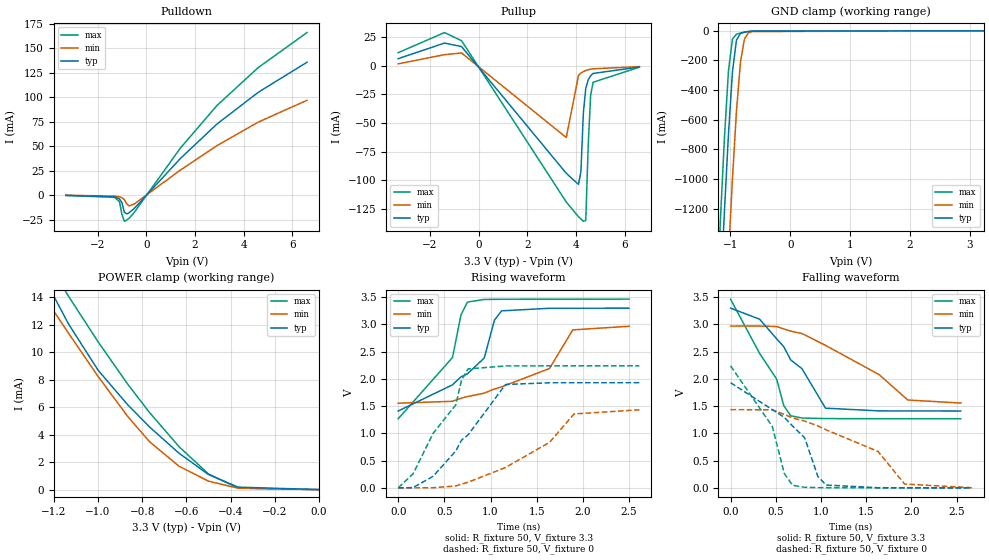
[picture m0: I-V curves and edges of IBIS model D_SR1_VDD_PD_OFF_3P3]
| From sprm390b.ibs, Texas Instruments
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|   Model Cell D_SR1_VDD_PD_OFF_3P3
|SR0_VDD_SR1_VDD_PD_OFF_3P3
[Model]   D_SR1_VDD_PD_OFF_3P3
Model_type   I/O
Polarity   Non-Inverting
Enable   Active-Low
Vinl =  0.8V
Vinh =  2V
Cref =  5.0000pF
Rref =  100.0000M
Vref =  0V
Vmeas =  1.65
C_comp   2.113745p   2.040636p   2.247812p
[Model Spec]
Vinl   0.8V   0.8V   0.8V
Vinh   2V   2V   2V
[Temperature Range]   25   125   -40
[Voltage Range]   3.3   2.97   3.465
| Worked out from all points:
|   slope of the pulldown table from 0 to 0.495 V, typ, clamps not added: 36.4 ohm
|   slope of the pullup table from 0 to 0.495 V, typ, clamps not added: 34.9 ohm
|   GND clamp passes 1 mA (typ) near -0.57 V on its own axis
|   POWER clamp passes 1 mA (typ) near -0.49 V on its own axis
|   rising waveform, R_fixture 50, V_fixture 3.3: 20-80 % time 540ps typ, 709ps min, 444ps max; typ from 1.41 V to 3.3 V
|   rising waveform, R_fixture 50, V_fixture 0: 20-80 % time 549ps typ, 739ps min, 445ps max; typ from 0 V to 1.93 V
|   falling waveform, R_fixture 50, V_fixture 3.3: 20-80 % time 516ps typ, 825ps min, 401ps max; typ from 3.3 V to 1.41 V
|   falling waveform, R_fixture 50, V_fixture 0: 20-80 % time 526ps typ, 842ps min, 409ps max; typ from 1.93 V to 0.001 V
[POWER_clamp]
|   voltage   I(typ)   I(min)   I(max)
-3.3V     86.08mA    64.51mA    104.3mA
-1.267V   16.23mA    14.61mA    17.94mA
-1.233V   15.14mA    13.79mA    16.86mA
-1.2V     14.07mA    12.98mA    15.86mA
-1.133V   12.04mA    11.37mA    14.06mA
-1V       8.693mA    8.239mA    10.76mA
-866.7mV  6.192mA    5.342mA    7.695mA
-766.7mV  4.556mA    3.483mA    5.603mA
-633.3mV  2.644mA    1.698mA    3.12mA
-500mV    1.095mA    613.6uA    1.135mA
-366.7mV  182uA      101.9uA    111.5uA
-11.55fV  514.4nA    479.6nA    539.8nA
[Pulldown]
|   voltage   I(typ)   I(min)   I(max)
-3.3V     -240.7uA   -171.6uA   -267.5uA
-1.3V     -1.697mA   -968uA     -2.239mA
-1.1V     -3.762mA   -1.687mA   -6.637mA
-1V       -7.728mA   -2.567mA   -19.64mA
-900mV    -17.44mA   -4.637mA   -26.73mA
-800mV    -19.19mA   -8.992mA   -25.39mA
-700mV    -17.88mA   -11mA      -23.57mA
-500mV    -13.74mA   -9.146mA   -17.83mA
1.4V      37.42mA    25.57mA    48.03mA
2.9V      72.6mA     50.52mA    91.53mA
4.6V      105.1mA    74.64mA    130.4mA
6.6V      135.8mA    96.92mA    166.1mA
[Pullup]
|   voltage   I(typ)   I(min)   I(max)
-3.3V     6.015mA    1.488mA    11.26mA
-1.4V     19.63mA    9.503mA    28.79mA
-700mV    16.55mA    11.01mA    21.71mA
3.6V      -93.97mA   -62.76mA   -119mA
4.1V      -103.6mA   -8.736mA   -131.8mA
4.2V      -92.66mA   -6.551mA   -133.7mA
4.3V      -41.55mA   -5.211mA   -135.8mA
4.4V      -19.91mA   -4.314mA   -135.1mA
4.5V      -12.4mA    -3.675mA   -69.72mA
4.6V      -8.869mA   -3.197mA   -25.86mA
4.7V      -6.864mA   -2.828mA   -14.55mA
6.6V      -1.25mA    -873.6uA   -1.41mA
[GND_clamp]
|   voltage   I(typ)   I(min)   I(max)
-3.3V     -22.46A    -23.25A    -22.02A
-1.233V   -2.372A    -3.255A    -1.856A
-1.167V   -1.78A     -2.658A    -1.268A
-1.1V     -1.214A    -2.077A    -719.3mA
-1.033V   -694.9mA   -1.519A    -269mA
-966.7mV  -277.7mA   -998.2mA   -54.76mA
-900mV    -62.9mA    -543.8mA   -23.12mA
-833.3mV  -17.79mA   -212.7mA   -15.05mA
-766.7mV  -9.259mA   -55.44mA   -9.031mA
-700mV    -5.097mA   -13.91mA   -4.436mA
-633.3mV  -2.354mA   -4.853mA   -1.588mA
3.233V    494nA      13.48uA    483nA
[Ramp]
| variable   typ   min   max
dV/dt_f   1.523549/0.6827238n   1.142886/1.116788n   1.769367/0.5163791n
dV/dt_r   1.547078/0.694645n   1.15064/0.965876n   1.794788/0.5501428n
R_load = 50
[Rising Waveform]
R_fixture = 50
V_fixture = 3.3
V_fixture_min = 2.97
V_fixture_max = 3.465
|   time   V(typ)   V(min)   V(max)
0s        1.411V     1.554V     1.269V
588ps     1.892V     1.59V      2.394V
679ps     2.038V     1.645V     3.174V
749ps     2.093V     1.676V     3.411V
931ps     2.383V     1.739V     3.459V
1.043ns   3.083V     1.816V     3.461V
1.12ns    3.25V      1.855V     3.462V
1.638ns   3.297V     2.191V     3.464V
1.89ns    3.298V     2.9V       3.464V
2.499ns   3.299V     2.967V     3.465V
[Rising Waveform]
R_fixture = 50
V_fixture = 0
V_fixture_min = 0
V_fixture_max = 0
|   time   V(typ)   V(min)   V(max)
0s        5.618uV    6.879uV    4.844uV
161ps     4.617mV    -39.37uV   258.5mV
378ps     212.5mV    2.905mV    1.001V
623ps     676.8mV    34.28mV    1.523V
686ps     876.2mV    69.87mV    1.98V
756ps     971.5mV    102.7mV    2.184V
1.162ns   1.898V     373.9mV    2.238V
1.638ns   1.929V     834.8mV    2.24V
1.904ns   1.93V      1.357V     2.241V
2.611ns   1.931V     1.433V     2.241V
[Falling Waveform]
R_fixture = 50
V_fixture = 3.3
V_fixture_min = 2.97
V_fixture_max = 3.465
|   time   V(typ)   V(min)   V(max)
0s        3.3V       2.97V      3.465V
322ps     3.096V     2.971V     2.467V
511ps     2.734V     2.962V     1.993V
588ps     2.594V     2.919V     1.513V
665ps     2.35V      2.878V     1.324V
791ps     2.186V     2.833V     1.282V
1.05ns    1.463V     2.616V     1.272V
1.645ns   1.413V     2.077V     1.27V
1.96ns    1.412V     1.613V     1.269V
2.548ns   1.411V     1.557V     1.269V
[Falling Waveform]
R_fixture = 50
V_fixture = 0
V_fixture_min = 0
V_fixture_max = 0
|   time   V(typ)   V(min)   V(max)
0s        1.931V     1.436V     2.241V
462ps     1.436V     1.434V     1.127V
595ps     1.295V     1.348V     263.1mV
686ps     1.135V     1.284V     47.65mV
819ps     922.6mV    1.226V     10.72mV
966ps     209.4mV    1.137V     5.024mV
1.057ns   52.32mV    1.066V     3.839mV
1.631ns   2.764mV    668.9mV    1.175mV
1.925ns   1.693mV    70.24mV    678.1uV
2.667ns   681.7uV    3mV        227.6uV
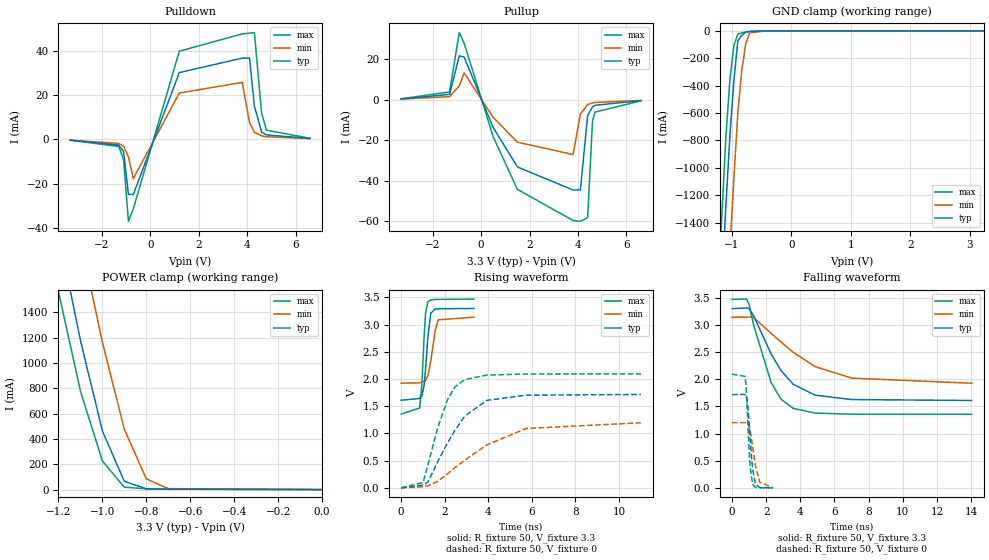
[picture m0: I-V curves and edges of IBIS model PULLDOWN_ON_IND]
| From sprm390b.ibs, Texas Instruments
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|   Model Cell PULLDOWN_ON_IND
[Model]   PULLDOWN_ON_IND
Model_type   I/O
Polarity   Non-Inverting
Enable   Active-Low
Vinl =  0.8
Vinh =  2
Cref =  15.0000pF
Rref =  100.0000M
Vref =  0V
Vmeas =  1.65
C_comp   0.8695239p   0.8584917p   0.8767336p
[Model Spec]
Vinl   0.8   0.8   0.8
Vinh   2   2   2
[Temperature Range]   25   125   -40
[Voltage Range]   3.3   3.14   3.47
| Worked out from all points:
|   slope of the pulldown table from 0 to 0.495 V, typ, clamps not added: 30.2 ohm
|   slope of the pullup table from 0 to 0.495 V, typ, clamps not added: 36.2 ohm
|   GND clamp passes 1 mA (typ) near -0.57 V on its own axis
|   POWER clamp passes 1 mA (typ) near -0.51 V on its own axis
|   rising waveform, R_fixture 50, V_fixture 3.3: 20-80 % time 196ps typ, 271ps min, 158ps max; typ from 1.61 V to 3.3 V
|   rising waveform, R_fixture 50, V_fixture 0: 20-80 % time 1.52ns typ, 2.63ns min, 970ps max; typ from 0 V to 1.72 V
|   falling waveform, R_fixture 50, V_fixture 3.3: 20-80 % time 1.92ns typ, 3.21ns min, 1.31ns max; typ from 3.3 V to 1.61 V
|   falling waveform, R_fixture 50, V_fixture 0: 20-80 % time 245ps typ, 360ps min, 192ps max; typ from 1.72 V to 0.002 V
[POWER_clamp]
|   voltage   I(typ)   I(min)   I(max)
-3.3V     22.37A     23.12A     21.96A
-1.2V     2.026A     2.853A     1.569A
-1.167V   1.745A     2.562A     1.307A
-1.133V   1.464A     2.272A     1.044A
-1.1V     1.183A     1.981A     781.9mA
-1.067V   943.8mA    1.709A     597.3mA
-1.033V   704.5mA    1.438A     412.6mA
-1V       465.3mA    1.167A     228mA
-900mV    65.82mA    478.8mA    19.1mA
-800mV    6.559mA    85.44mA    6.233mA
-700mV    3.243mA    7.603mA    3.974mA
-11.55fV  93.69uA    58.38uA    142.7uA
[Pulldown]
|   voltage   I(typ)   I(min)   I(max)
-3.3V     -379.4uA   -343.9uA   -387.1uA
-1.3V     -2.568mA   -1.817mA   -3.182mA
-1.1V     -5.533mA   -3.077mA   -9.169mA
-900mV    -24.8mA    -7.917mA   -37.01mA
-700mV    -24.92mA   -17.73mA   -31.42mA
1.2V      30.21mA    20.95mA    39.85mA
3.8V      36.73mA    25.77mA    47.69mA
4.1V      36.79mA    7.552mA    48.04mA
4.3V      15.06mA    3.224mA    48.29mA
4.6V      3.307mA    1.638mA    11.86mA
4.8V      2.043mA    1.221mA    4.171mA
6.6V      436uA      362.2uA    504.7uA
[Pullup]
|   voltage   I(typ)   I(min)   I(max)
-3.3V     352.6uA    265.5uA    392uA
-1.3V     2.559mA    1.454mA    3.793mA
-900mV    21.62mA    6.762mA    33.1mA
-700mV    21.01mA    13.2mA     27.87mA
500mV     -13.79mA   -8.778mA   -18.37mA
1.5V      -33.25mA   -21.03mA   -44.32mA
3.8V      -44.66mA   -27.13mA   -59.69mA
4.1V      -44.61mA   -7.119mA   -60.09mA
4.4V      -7.897mA   -2.442mA   -58.25mA
4.6V      -3.604mA   -1.655mA   -10.86mA
4.7V      -2.803mA   -1.422mA   -6.172mA
6.6V      -515.4uA   -377.6uA   -600.5uA
[GND_clamp]
|   voltage   I(typ)   I(min)   I(max)
-3.3V     -22.52A    -23.33A    -22.07A
-1.233V   -2.436A    -3.336A    -1.911A
-1.167V   -1.845A    -2.739A    -1.328A
-1.1V     -1.269A    -2.151A    -766.5mA
-1.033V   -763.9mA   -1.597A    -354.9mA
-966.7mV  -365.3mA   -1.079A    -107.2mA
-900mV    -73.59mA   -596.9mA   -23.38mA
-833.3mV  -32.67mA   -287.4mA   -15.4mA
-766.7mV  -9.715mA   -93.52mA   -8.973mA
-700mV    -4.738mA   -15.15mA   -4.098mA
-433.3mV  -102.5uA   -290.5uA   -69.12uA
3.233V    93.67uA    58.63uA    142.6uA
[Ramp]
| variable   typ   min   max
dV/dt_f   1.02374/1.926598n   0.737575/3.244975n   1.279266/1.316571n
dV/dt_r   1.030118/1.522336n   0.7199978/2.644106n   1.255922/0.9676829n
R_load = 50
[Rising Waveform]
R_fixture = 50
V_fixture = 3.3
V_fixture_min = 3.14
V_fixture_max = 3.47
|   time   V(typ)   V(min)   V(max)
0s        1.609V     1.923V     1.354V
848ps     1.642V     1.929V     1.467V
948ps     1.683V     1.941V     1.875V
1.052ns   1.874V     1.954V     2.753V
1.12ns    2.174V     1.971V     3.209V
1.224ns   2.754V     2.053V     3.415V
1.36ns    3.209V     2.326V     3.453V
1.564ns   3.285V     2.894V     3.46V
1.7ns     3.289V     3.087V     3.462V
3.344ns   3.296V     3.135V     3.467V
[Rising Waveform]
R_fixture = 50
V_fixture = 0
V_fixture_min = 0
V_fixture_max = 0
|   time   V(typ)   V(min)   V(max)
0s        97.34nV    406.4nV    8.356nV
1.008ns   51.54mV    21.89mV    99mV
1.232ns   107mV      40.68mV    429.3mV
1.68ns    481.7mV    118.7mV    1.104V
2.132ns   827.1mV    258.8mV    1.62V
2.468ns   1.055V     371.2mV    1.855V
2.92ns    1.317V     507.4mV    1.988V
3.928ns   1.607V     788mV      2.072V
5.728ns   1.702V     1.09V      2.091V
11.01ns   1.716V     1.196V     2.093V
[Falling Waveform]
R_fixture = 50
V_fixture = 3.3
V_fixture_min = 3.14
V_fixture_max = 3.47
|   time   V(typ)   V(min)   V(max)
0s        3.298V     3.139V     3.468V
856ps     3.311V     3.139V     3.473V
1ns       3.301V     3.148V     3.376V
1.284ns   3.156V     3.132V     2.977V
2.288ns   2.467V     2.844V     1.943V
2.864ns   2.163V     2.687V     1.633V
3.58ns    1.908V     2.496V     1.464V
4.868ns   1.706V     2.231V     1.377V
7.02ns    1.625V     2.02V      1.356V
14.04ns   1.609V     1.926V     1.354V
[Falling Waveform]
R_fixture = 50
V_fixture = 0
V_fixture_min = 0
V_fixture_max = 0
|   time   V(typ)   V(min)   V(max)
0s        1.716V     1.2V       2.093V
760ps     1.721V     1.2V       2.053V
832ps     1.688V     1.206V     1.849V
908ps     1.562V     1.199V     1.351V
980ps     1.301V     1.162V     825.2mV
1.056ns   933.4mV    1.074V     414.6mV
1.204ns   354.8mV    773.8mV    67.14mV
1.376ns   71.13mV    401.4mV    9.308mV
1.624ns   7.627mV    104.3mV    3.273mV
2.408ns   1.889mV    3.168mV    1.257mV
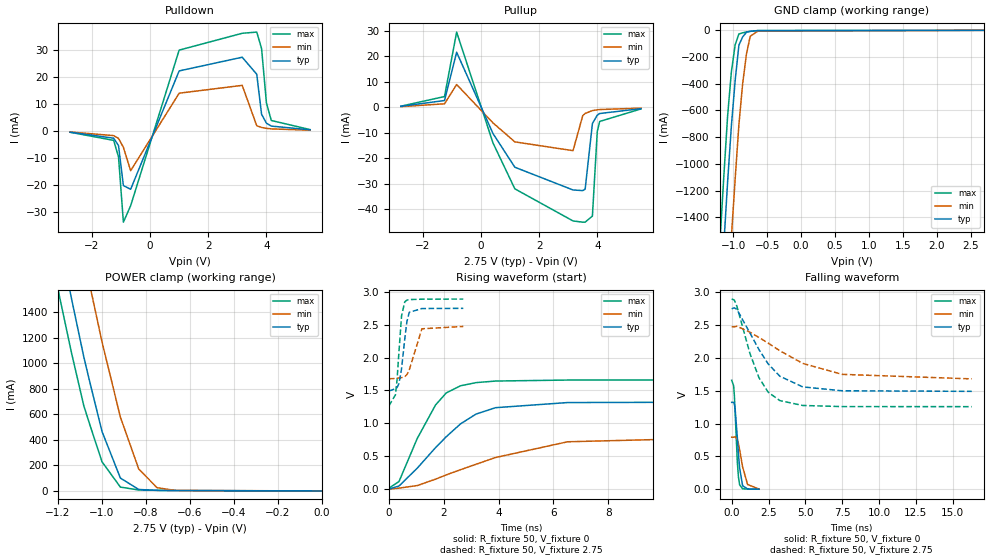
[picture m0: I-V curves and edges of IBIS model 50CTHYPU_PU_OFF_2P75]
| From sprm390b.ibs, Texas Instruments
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|   Model Cell 50CTHYPU_PU_OFF_2P75
|BC3350CTHYPU_PU_OFF_2P75
[Model]   50CTHYPU_PU_OFF_2P75
Model_type   I/O
Polarity   Non-Inverting
Enable   Active-Low
Vinl =  0.7V
Vinh =  1.7V
Cref =  15.0000pF
Rref =  100.0000M
Vref =  0V
Vmeas =  1.375
C_comp   0.8815254p   0.8700002p   0.8886429p
[Model Spec]
Vinl   0.7V   0.7V   0.7V
Vinh   1.7V   1.7V   1.7V
[Temperature Range]   25   125   -40
[Voltage Range]   2.75   2.475   2.89
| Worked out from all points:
|   slope of the pulldown table from 0 to 0.412 V, typ, clamps not added: 34.2 ohm
|   slope of the pullup table from 0 to 0.412 V, typ, clamps not added: 40.5 ohm
|   GND clamp passes 1 mA (typ) near -0.59 V on its own axis
|   POWER clamp passes 1 mA (typ) near -0.52 V on its own axis
|   rising waveform, R_fixture 50, V_fixture 0: 20-80 % time 1.9ns typ, 3.45ns min, 1.19ns max; typ from 0.002 V to 1.32 V
|   rising waveform, R_fixture 50, V_fixture 2.75: 20-80 % time 207ps typ, 302ps min, 164ps max; typ from 1.49 V to 2.75 V
|   falling waveform, R_fixture 50, V_fixture 0: 20-80 % time 263ps typ, 414ps min, 202ps max; typ from 1.32 V to 0.001 V
|   falling waveform, R_fixture 50, V_fixture 2.75: 20-80 % time 2.21ns typ, 3.92ns min, 1.52ns max; typ from 2.75 V to 1.49 V
[POWER_clamp]
|   voltage   I(typ)   I(min)   I(max)
-2.75V    16.94A     17.72A     16.52A
-1.194V   1.981A     2.806A     1.529A
-1.139V   1.509A     2.319A     1.084A
-1.083V   1.051A     1.84A      668.4mA
-1.056V   856mA      1.616A     521.6mA
-1.028V   660.7mA    1.391A     374.8mA
-1V       465.3mA    1.167A     228mA
-916.7mV  101mA      578.9mA    30.09mA
-833.3mV  11.44mA    171.8mA    7.269mA
-750mV    4.145mA    25.43mA    4.878mA
-666.7mV  2.649mA    3.757mA    3.2mA
0V        162.7pA    10.29nA    5.769pA
[Pulldown]
|   voltage   I(typ)   I(min)   I(max)
-2.75V    -442uA     -372.3uA   -461.5uA
-1.25V    -2.654mA   -1.707mA   -3.464mA
-1.083V   -5.414mA   -2.743mA   -9.571mA
-916.7mV  -20.11mA   -6.002mA   -33.59mA
-666.7mV  -21.47mA   -14.63mA   -27.52mA
1V        22.12mA    13.91mA    29.78mA
3.167V    27.16mA    16.8mA     35.98mA
3.667V    20.89mA    1.926mA    36.42mA
3.833V    6.158mA    1.295mA    30.36mA
4V        2.871mA    968.4uA    10.33mA
4.167V    1.802mA    770.5uA    3.863mA
5.5V      426.6uA    287.2uA    512.6uA
[Pullup]
|   voltage   I(typ)   I(min)   I(max)
-2.75V    418.2uA    298uA      474.9uA
-1.25V    2.701mA    1.416mA    4.261mA
-833.3mV  21.66mA    8.993mA    29.57mA
416.7mV   -10.28mA   -6.093mA   -13.97mA
1.167V    -23.49mA   -13.53mA   -31.97mA
3.167V    -32.42mA   -16.99mA   -44.58mA
3.5V      -32.66mA   -3.265mA   -45.07mA
3.583V    -32.13mA   -2.367mA   -45.05mA
3.833V    -6.324mA   -1.256mA   -42.67mA
4V        -3.056mA   -947.9uA   -9.45mA
4.083V    -2.401mA   -843.3uA   -5.52mA
5.5V      -494.4uA   -288.5uA   -602.6uA
[GND_clamp]
|   voltage   I(typ)   I(min)   I(max)
-2.75V    -17.09A    -17.92A    -16.63A
-1.194V   -2.087A    -2.985A    -1.564A
-1.139V   -1.603A    -2.493A    -1.092A
-1.083V   -1.133A    -2.009A    -639.3mA
-1.028V   -718.3mA   -1.55A     -312.4mA
-972.2mV  -377.6mA   -1.115A    -108.5mA
-916.7mV  -110.7mA   -705.2mA   -27.3mA
-861.1mV  -49.11mA   -398.2mA   -18.78mA
-805.6mV  -14.74mA   -178.1mA   -12.09mA
-750mV    -7.591mA   -44.83mA   -7.219mA
-638.9mV  -2.45mA    -6.091mA   -1.79mA
2.694V    -702.7pA   3.82uA     -24.74pA
[Ramp]
| variable   typ   min   max
dV/dt_f  0.7639975/2.221425n   0.484314/3.981112n   0.9885609/1.527353n
dV/dt_r  0.7939505/1.902615n   0.4756004/3.465002n   0.995026/1.20094n
R_load = 50
[Rising Waveform]
R_fixture = 50
V_fixture = 0
V_fixture_min = 0
V_fixture_max = 0
|   time   V(typ)   V(min)   V(max)
0s        1.783mV    -423.2uV   15.25mV
369ps     47.28mV    15.33mV    115.1mV
1.035ns   318.9mV    54.42mV    770.3mV
1.701ns   630.6mV    151.4mV    1.279V
2.091ns   796.5mV    216.3mV    1.462V
2.613ns   992.2mV    295.6mV    1.571V
3.177ns   1.141V     378mV      1.619V
3.888ns   1.238V     480.6mV    1.643V
6.516ns   1.316V     719.9mV    1.658V
13.17ns   1.323V     789.7mV    1.658V
[Rising Waveform]
R_fixture = 50
V_fixture = 2.75
V_fixture_min = 2.475
V_fixture_max = 2.89
|   time   V(typ)   V(min)   V(max)
0s        1.491V     1.678V     1.264V
240ps     1.526V     1.682V     1.433V
297ps     1.543V     1.686V     1.655V
369ps     1.607V     1.69V      2.093V
462ps     1.828V     1.694V     2.631V
579ps     2.278V     1.708V     2.846V
657ps     2.546V     1.741V     2.873V
744ps     2.688V     1.812V     2.881V
1.203ns   2.745V     2.437V     2.887V
2.712ns   2.748V     2.473V     2.889V
[Falling Waveform]
R_fixture = 50
V_fixture = 0
V_fixture_min = 0
V_fixture_max = 0
|   time   V(typ)   V(min)   V(max)
0s        1.323V     792.3mV    1.66V
132ps     1.324V     792.8mV    1.577V
183ps     1.294V     796.6mV    1.421V
234ps     1.223V     800.6mV    1.17V
384ps     782.4mV    758.4mV    408.7mV
459ps     535.2mV    693.9mV    185.2mV
537ps     324.1mV    604.2mV    67.81mV
741ps     52.77mV    341.3mV    6.665mV
1.077ns   3.649mV    72.65mV    1.896mV
1.851ns   1.319mV    2.486mV    950.3uV
[Falling Waveform]
R_fixture = 50
V_fixture = 2.75
V_fixture_min = 2.475
V_fixture_max = 2.89
|   time   V(typ)   V(min)   V(max)
0s        2.749V     2.475V     2.897V
177ps     2.764V     2.475V     2.883V
354ps     2.739V     2.483V     2.786V
1.236ns   2.382V     2.393V     2.07V
1.854ns   2.126V     2.311V     1.698V
2.478ns   1.909V     2.226V     1.478V
3.273ns   1.721V     2.109V     1.35V
4.824ns   1.559V     1.917V     1.276V
7.491ns   1.5V       1.75V      1.259V
16.3ns    1.491V     1.681V     1.258V
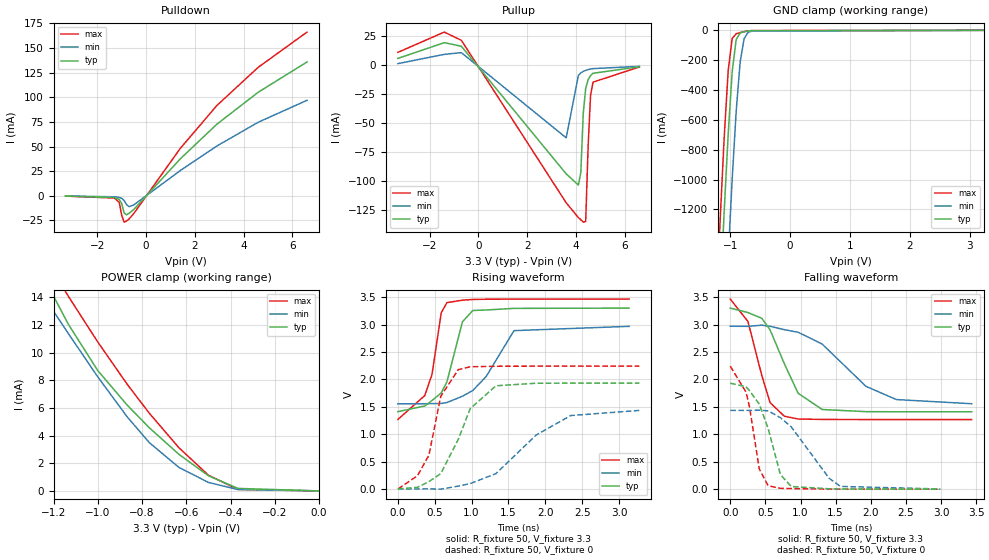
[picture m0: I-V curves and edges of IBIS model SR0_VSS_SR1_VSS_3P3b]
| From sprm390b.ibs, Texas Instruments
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|   Model Cell SR0_VSS_SR1_VSS_3P3b
|SR0_VSS_SR1_VSS_3P3b
[Model]   SR0_VSS_SR1_VSS_3P3b
Model_type   3-state
Polarity   Non-Inverting
Enable   Active-Low
Cref =  5.0000pF
Rref =  100.0000M
Vref =  0V
Vmeas =  1.65
C_comp   1.985348p   1.918512p   2.114271p
[Temperature Range]   25   125   -40
[Voltage Range]   3.3   2.97   3.465
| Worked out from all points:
|   slope of the pulldown table from 0 to 0.495 V, typ, clamps not added: 36.4 ohm
|   slope of the pullup table from 0 to 0.495 V, typ, clamps not added: 34.9 ohm
|   GND clamp passes 1 mA (typ) near -0.57 V on its own axis
|   POWER clamp passes 1 mA (typ) near -0.49 V on its own axis
|   rising waveform, R_fixture 50, V_fixture 3.3: 20-80 % time 242ps typ, 386ps min, 195ps max; typ from 1.41 V to 3.3 V
|   rising waveform, R_fixture 50, V_fixture 0: 20-80 % time 388ps typ, 793ps min, 259ps max; typ from 0 V to 1.93 V
|   falling waveform, R_fixture 50, V_fixture 3.3: 20-80 % time 385ps typ, 713ps min, 261ps max; typ from 3.3 V to 1.41 V
|   falling waveform, R_fixture 50, V_fixture 0: 20-80 % time 267ps typ, 495ps min, 183ps max; typ from 1.93 V to 0 V
[POWER_clamp]
|   voltage   I(typ)   I(min)   I(max)
-3.3V     86.08mA    64.51mA    104.3mA
-1.267V   16.23mA    14.61mA    17.94mA
-1.233V   15.14mA    13.79mA    16.86mA
-1.2V     14.07mA    12.98mA    15.86mA
-1.133V   12.04mA    11.37mA    14.06mA
-1V       8.693mA    8.239mA    10.76mA
-866.7mV  6.192mA    5.342mA    7.695mA
-766.7mV  4.556mA    3.483mA    5.603mA
-633.3mV  2.644mA    1.698mA    3.12mA
-500mV    1.095mA    613.5uA    1.135mA
-366.7mV  181.9uA    101.9uA    111.4uA
-11.55fV  449.1nA    420.7nA    471.2nA
[Pulldown]
|   voltage   I(typ)   I(min)   I(max)
-3.3V     -240.7uA   -171.6uA   -267.4uA
-1.3V     -1.696mA   -967.9uA   -2.238mA
-1.1V     -3.76mA    -1.687mA   -6.633mA
-1V       -7.724mA   -2.566mA   -19.64mA
-900mV    -17.44mA   -4.636mA   -26.73mA
-800mV    -19.19mA   -8.992mA   -25.4mA
-700mV    -17.88mA   -11mA      -23.57mA
-500mV    -13.74mA   -9.146mA   -17.83mA
1.4V      37.42mA    25.57mA    48.03mA
2.9V      72.6mA     50.52mA    91.53mA
4.6V      105.1mA    74.64mA    130.4mA
6.6V      135.8mA    96.92mA    166.1mA
[Pullup]
|   voltage   I(typ)   I(min)   I(max)
-3.3V     6.015mA    1.488mA    11.26mA
-1.4V     19.63mA    9.503mA    28.79mA
-700mV    16.55mA    11.01mA    21.71mA
3.6V      -93.97mA   -62.77mA   -119mA
4.1V      -103.6mA   -8.734mA   -131.8mA
4.2V      -92.67mA   -6.55mA    -133.7mA
4.3V      -41.54mA   -5.211mA   -135.8mA
4.4V      -19.9mA    -4.314mA   -135.1mA
4.5V      -12.39mA   -3.675mA   -69.69mA
4.6V      -8.867mA   -3.197mA   -25.85mA
4.7V      -6.863mA   -2.828mA   -14.55mA
6.6V      -1.25mA    -873.6uA   -1.41mA
[GND_clamp]
|   voltage   I(typ)   I(min)   I(max)
-3.3V     -22.46A    -23.25A    -22.02A
-1.233V   -2.372A    -3.255A    -1.856A
-1.167V   -1.78A     -2.658A    -1.268A
-1.1V     -1.214A    -2.077A    -719.1mA
-1.033V   -694.7mA   -1.519A    -268.7mA
-966.7mV  -277.4mA   -998mA     -54.36mA
-900mV    -62.56mA   -543.6mA   -22.84mA
-833.3mV  -17.57mA   -212.4mA   -14.86mA
-766.7mV  -9.139mA   -55.16mA   -8.916mA
-700mV    -5.031mA   -13.73mA   -4.378mA
-633.3mV  -2.323mA   -4.775mA   -1.567mA
3.233V    432.4nA    13.42uA    421.6nA
[Ramp]
| variable   typ   min   max
dV/dt_f   1.530464/0.7199307n   1.148231/1.235745n   1.776643/0.487722n
dV/dt_r   1.548611/0.6629815n   1.151958/1.135901n   1.796347/0.4633357n
R_load = 50
[Rising Waveform]
R_fixture = 50
V_fixture = 3.3
V_fixture_min = 2.97
V_fixture_max = 3.465
|   time   V(typ)   V(min)   V(max)
0s        1.411V     1.554V     1.269V
364ps     1.514V     1.555V     1.704V
462ps     1.614V     1.557V     2.085V
588ps     1.753V     1.56V      3.216V
665ps     1.955V     1.577V     3.4V
875ps     3.049V     1.692V     3.444V
1.015ns   3.256V     1.795V     3.458V
1.197ns   3.266V     2.051V     3.462V
1.575ns   3.295V     2.889V     3.464V
3.136ns   3.3V       2.967V     3.465V
[Rising Waveform]
R_fixture = 50
V_fixture = 0
V_fixture_min = 0
V_fixture_max = 0
|   time   V(typ)   V(min)   V(max)
0s        5.618uV    6.875uV    4.844uV
266ps     30.79mV    72.58uV    242.6mV
420ps     133.6mV    2.188mV    614.6mV
581ps     280.4mV    -3.633mV   1.69V
819ps     904.9mV    52.2mV     2.178V
980ps     1.465V     97.29mV    2.229V
1.33ns    1.883V     280.4mV    2.239V
1.876ns   1.929V     984mV      2.241V
2.345ns   1.931V     1.34V      2.241V
3.276ns   1.931V     1.433V     2.241V
[Falling Waveform]
R_fixture = 50
V_fixture = 3.3
V_fixture_min = 2.97
V_fixture_max = 3.465
|   time   V(typ)   V(min)   V(max)
0s        3.3V       2.97V      3.465V
252ps     3.219V     2.968V     3.055V
448ps     3.116V     2.989V     2.077V
567ps     2.903V     2.969V     1.578V
770ps     2.286V     2.907V     1.329V
966ps     1.748V     2.86V      1.279V
1.309ns   1.452V     2.644V     1.271V
1.932ns   1.413V     1.874V     1.269V
2.366ns   1.411V     1.633V     1.269V
3.437ns   1.411V     1.557V     1.269V
[Falling Waveform]
R_fixture = 50
V_fixture = 0
V_fixture_min = 0
V_fixture_max = 0
|   time   V(typ)   V(min)   V(max)
0s        1.931V     1.436V     2.241V
224ps     1.867V     1.436V     1.77V
273ps     1.797V     1.435V     1.508V
413ps     1.55V      1.439V     369.1mV
539ps     1.107V     1.428V     62.45mV
714ps     265.4mV    1.303V     16.04mV
868ps     48.31mV    1.136V     10.91mV
1.407ns   7.037mV    199.8mV    1.412mV
1.568ns   3.72mV     50.35mV    1.007mV
2.989ns   356.1uV    3.011mV    120.3uV
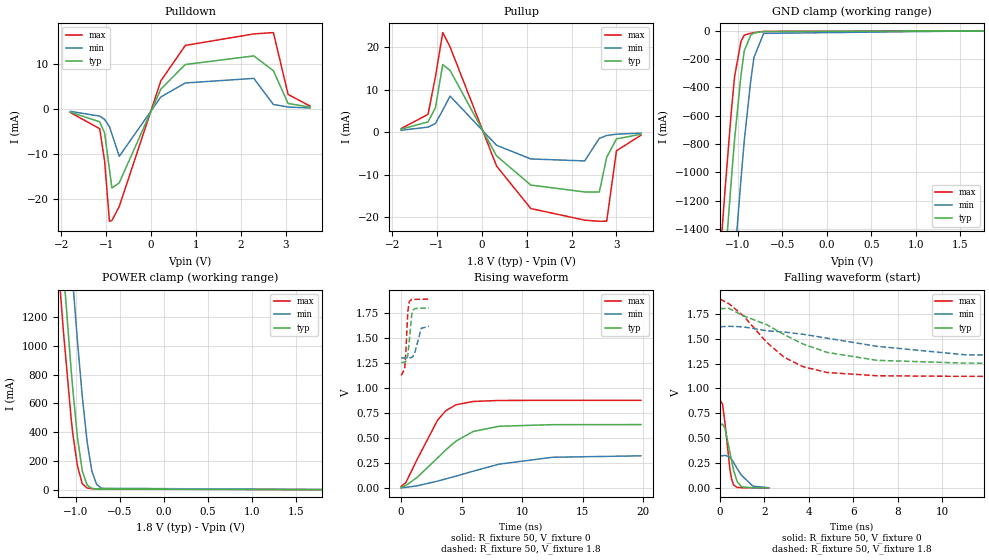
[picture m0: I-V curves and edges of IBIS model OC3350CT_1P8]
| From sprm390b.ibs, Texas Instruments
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|   Model Cell OC3350CT_1P8
|OC3350CT_1P8
[Model]   OC3350CT_1P8
Model_type   3-state
Polarity   Non-Inverting
Enable   Active-Low
Cref =  15.0000pF
Rref =  100.0000M
Vref =  0V
Vmeas =  0.9
C_comp   1.382326p   1.367102p   1.400048p
[Temperature Range]   25   125   -40
[Voltage Range]   1.8   1.62   1.89
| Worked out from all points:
|   slope of the pulldown table from 0 to 0.27 V, typ, clamps not added: 51 ohm
|   slope of the pullup table from 0 to 0.27 V, typ, clamps not added: 57.1 ohm
|   GND clamp passes 1 mA (typ) near -0.58 V on its own axis
|   POWER clamp passes 1 mA (typ) near -0.52 V on its own axis
|   rising waveform, R_fixture 50, V_fixture 0: 20-80 % time 3.47ns typ, 5.93ns min, 2.23ns max; typ from 0.003 V to 0.633 V
|   rising waveform, R_fixture 50, V_fixture 1.8: 20-80 % time 244ps typ, 383ps min, 186ps max; typ from 1.25 V to 1.8 V
|   falling waveform, R_fixture 50, V_fixture 0: 20-80 % time 350ps typ, 587ps min, 253ps max; typ from 0.633 V to 0.001 V
|   falling waveform, R_fixture 50, V_fixture 1.8: 20-80 % time 3.19ns typ, 5.95ns min, 2.16ns max; typ from 1.8 V to 1.25 V
[POWER_clamp]
|   voltage   I(typ)   I(min)   I(max)
-1.8V     7.656A     8.472A     7.195A
-1.2V     2.026A     2.853A     1.569A
-1.145V   1.557A     2.372A     1.122A
-1.055V   838.8mA    1.603A     500.9mA
-1.036V   702.8mA    1.453A     391.9mA
-981.8mV  361.3mA    1.029A     163mA
-927.3mV  130mA      646.3mA    41.08mA
-872.7mV  30.94mA    333.2mA    10.81mA
-818.2mV  8.508mA    126.9mA    6.655mA
-763.6mV  4.54mA     35.71mA    5.182mA
-709.1mV  3.3mA      9.311mA    4.013mA
1.8V      61.88pA    6.338nA    974.8fA
[Pulldown]
|   voltage   I(typ)   I(min)   I(max)
-1.8V     -681.8uA   -516.5uA   -765.3uA
-1.145V   -2.845mA   -1.565mA   -4.38mA
-1.036V   -5.31mA    -2.287mA   -11.57mA
-927.3mV  -13.49mA   -3.929mA   -25.01mA
-872.7mV  -17.58mA   -5.575mA   -24.82mA
-709.1mV  -16.44mA   -10.53mA   -21.73mA
218.2mV   4.45mA     2.706mA    6.292mA
763.6mV   9.932mA    5.814mA    14.18mA
2.291V    11.85mA    6.843mA    16.75mA
2.727V    8.542mA    1.025mA    17.05mA
3.055V    1.241mA    457.6uA    3.265mA
3.545V    447.3uA    243.5uA    654.8uA
[Pullup]
|   voltage   I(typ)   I(min)   I(max)
-1.8V     683.6uA    441.3uA    848.3uA
-1.2V     2.423mA    1.182mA    4.185mA
-1.036V   5.748mA    2.058mA    13.02mA
-872.7mV  15.88mA    5.165mA    23.42mA
-709.1mV  14.53mA    8.476mA    20.05mA
327.3mV   -5.597mA   -3.09mA    -7.989mA
1.091V    -12.45mA   -6.301mA   -17.97mA
2.291V    -14.07mA   -6.771mA   -20.7mA
2.618V    -14.08mA   -1.459mA   -20.97mA
2.782V    -5.907mA   -790.8uA   -20.94mA
3V        -1.581mA   -477.1uA   -4.381mA
3.545V    -498.1uA   -234.4uA   -720.3uA
[GND_clamp]
|   voltage   I(typ)   I(min)   I(max)
-1.8V     -7.797A    -8.671A    -7.298A
-1.218V   -2.297A    -3.197A    -1.772A
-1.182V   -1.974A    -2.871A    -1.452A
-1.145V   -1.654A    -2.548A    -1.137A
-1.073V   -1.052A    -1.92A     -571.7mA
-1.036V   -766.2mA   -1.614A    -322.7mA
-963.6mV  -312.1mA   -1.044A    -73.06mA
-927.3mV  -141.8mA   -777.2mA   -30.72mA
-854.5mV  -30.23mA   -352.5mA   -16.79mA
-818.2mV  -14.75mA   -187.7mA   -12.85mA
-709.1mV  -5.072mA   -18.07mA   -4.464mA
1.764V    -762.7pA   512.2nA    -26.25pA
[Ramp]
| variable   typ   min   max
dV/dt_f   0.33464/3.233936n   0.1954969/6.143692n   0.4675718/2.168199n
dV/dt_r  0.3801174/3.486218n   0.1934224/5.977375n   0.5258748/2.25081n
R_load = 50
[Rising Waveform]
R_fixture = 50
V_fixture = 0
V_fixture_min = 0
V_fixture_max = 0
|   time   V(typ)   V(min)   V(max)
0s        3.176mV    -371.4uV   14.12mV
393ps     23.61mV    4.603mV    52.87mV
1.308ns   102.9mV    19.61mV    281.4mV
3.009ns   299.1mV    67.02mV    676.5mV
3.693ns   379.6mV    89.76mV    772.5mV
4.518ns   466.5mV    116.4mV    830.5mV
5.946ns   563.6mV    166.2mV    864.6mV
8.082ns   616.4mV    236.8mV    874.5mV
12.51ns   632.2mV    305.9mV    876mV
19.82ns   633mV      320.3mV    876mV
[Rising Waveform]
R_fixture = 50
V_fixture = 1.8
V_fixture_min = 1.62
V_fixture_max = 1.89
|   time   V(typ)   V(min)   V(max)
0s        1.251V     1.3V       1.125V
291ps     1.26V      1.3V       1.189V
378ps     1.264V     1.3V       1.334V
549ps     1.323V     1.301V     1.759V
669ps     1.464V     1.301V     1.865V
867ps     1.725V     1.305V     1.886V
972ps     1.779V     1.315V     1.887V
1.146ns   1.795V     1.361V     1.887V
1.662ns   1.798V     1.597V     1.888V
2.304ns   1.798V     1.618V     1.889V
[Falling Waveform]
R_fixture = 50
V_fixture = 0
V_fixture_min = 0
V_fixture_max = 0
|   time   V(typ)   V(min)   V(max)
0s        633.3mV    322.1mV    881.2mV
114ps     641.1mV    322.4mV    842.4mV
225ps     599.4mV    328.3mV    650.5mV
450ps     352.6mV    308.9mV    179.1mV
525ps     266.1mV    286.9mV    86.42mV
612ps     177.1mV    255.8mV    30.1mV
771ps     64.13mV    194.9mV    5.428mV
963ps     11.04mV    127.9mV    1.916mV
1.482ns   1.16mV     17.86mV    1.015mV
2.187ns   819.6uV    1.629mV    663.4uV
[Falling Waveform]
R_fixture = 50
V_fixture = 1.8
V_fixture_min = 1.62
V_fixture_max = 1.89
|   time   V(typ)   V(min)   V(max)
0s        1.801V     1.619V     1.897V
393ps     1.805V     1.624V     1.852V
1.05ns    1.73V      1.618V     1.73V
2.103ns   1.64V      1.579V     1.462V
2.889ns   1.54V      1.566V     1.312V
3.732ns   1.446V     1.544V     1.218V
4.809ns   1.362V     1.505V     1.16V
7.053ns   1.282V     1.423V     1.127V
11ns      1.254V     1.338V     1.121V
22.88ns   1.251V     1.301V     1.121V
